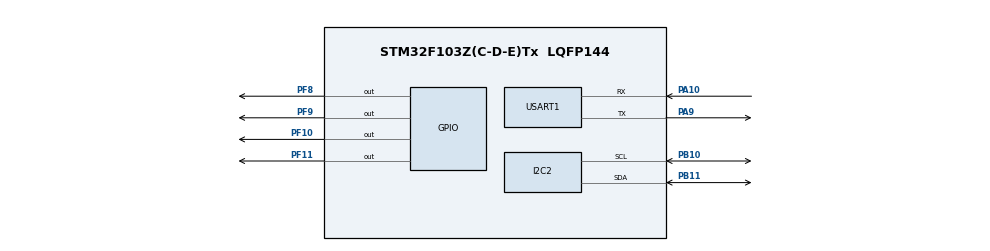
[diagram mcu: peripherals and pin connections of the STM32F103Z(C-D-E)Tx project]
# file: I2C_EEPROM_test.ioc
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I2C2.I2C_Mode=I2C_Fast
Mcu.Family=STM32F1
Mcu.Name=STM32F103Z(C-D-E)Tx
Mcu.Package=LQFP144
NVIC.PriorityGroup=NVIC_PRIORITYGROUP_4
OSC_IN.Mode=HSE-External-Oscillator
OSC_IN.Signal=RCC_OSC_IN
OSC_OUT.Mode=HSE-External-Oscillator
OSC_OUT.Signal=RCC_OSC_OUT
PA10.Mode=Asynchronous
PA10.Signal=USART1_RX
PA13.Mode=Serial_Wire
PA13.Signal=SYS_JTMS-SWDIO
PA14.Mode=Serial_Wire
PA14.Signal=SYS_JTCK-SWCLK
PA9.Mode=Asynchronous
PA9.Signal=USART1_TX
PB10.Mode=I2C
PB10.Signal=I2C2_SCL
PB11.Mode=I2C
PB11.Signal=I2C2_SDA
PF10.GPIO_ModeDefaultOutputPP=GPIO_MODE_OUTPUT_OD
PF10.GPIO_PuPd=GPIO_NOPULL
PF10.PinState=GPIO_PIN_SET
PF10.Signal=GPIO_Output
PF11.GPIO_ModeDefaultOutputPP=GPIO_MODE_OUTPUT_OD
PF11.GPIO_PuPd=GPIO_NOPULL
PF11.PinState=GPIO_PIN_SET
PF11.Signal=GPIO_Output
PF8.GPIO_ModeDefaultOutputPP=GPIO_MODE_OUTPUT_OD
PF8.GPIO_PuPd=GPIO_NOPULL
PF8.PinState=GPIO_PIN_SET
PF8.Signal=GPIO_Output
PF9.GPIO_ModeDefaultOutputPP=GPIO_MODE_OUTPUT_OD
PF9.GPIO_PuPd=GPIO_NOPULL
PF9.PinState=GPIO_PIN_SET
PF9.Signal=GPIO_Output
ProjectManager.HeapSize=0x200
ProjectManager.StackSize=0x400
ProjectManager.TargetToolchain=MDK-ARM V5.32
RCC.AHBFreq_Value=72000000
RCC.APB1CLKDivider=RCC_HCLK_DIV2
RCC.APB1Freq_Value=36000000
RCC.APB1TimFreq_Value=72000000
RCC.APB2Freq_Value=72000000
RCC.APB2TimFreq_Value=72000000
RCC.HCLKFreq_Value=72000000
RCC.PLLMUL=RCC_PLL_MUL9
RCC.PLLSourceVirtual=RCC_PLLSOURCE_HSE
RCC.SYSCLKFreq_VALUE=72000000
RCC.SYSCLKSource=RCC_SYSCLKSOURCE_PLLCLK
RCC.USBFreq_Value=72000000
USART1.Parity=PARITY_ODD
USART1.VirtualMode=VM_ASYNC
USART1.WordLength=WORDLENGTH_9B
board=custom

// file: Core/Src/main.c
/* USER CODE BEGIN Header */
/**
  ******************************************************************************
  * @file           : main.c
  * @brief          : Main program body
  ******************************************************************************
  * @attention
  *
  * Copyright (c) 2026 STMicroelectronics.
  * All rights reserved.
  *
  * This software is licensed under terms that can be found in the LICENSE file
  * in the root directory of this software component.
  * If no LICENSE file comes with this software, it is provided AS-IS.
  *
  ******************************************************************************
  */
/* USER CODE END Header */
#include "main.h"

/* USER CODE BEGIN Includes */
#include "APP.h"
/* USER CODE END Includes */

I2C_HandleTypeDef hi2c2;

UART_HandleTypeDef huart1;

void SystemClock_Config(void);
static void MX_GPIO_Init(void);
static void MX_I2C2_Init(void);
static void MX_USART1_UART_Init(void);

int main(void)
{

  /* MCU Configuration--------------------------------------------------------*/

  /* Reset of all peripherals, Initializes the Flash interface and the Systick. */
  HAL_Init();

  /* Configure the system clock */
  SystemClock_Config();

  /* Initialize all configured peripherals */
  MX_GPIO_Init();
  MX_I2C2_Init();
  MX_USART1_UART_Init();
  /* USER CODE BEGIN 2 */
  BSP_Usart_Init(&huart1);
  App_Init();
  /* USER CODE END 2 */

  /* Infinite loop */
  while (1)
  {

  }
}

void SystemClock_Config(void)
{
  RCC_OscInitTypeDef RCC_OscInitStruct = {0};
  RCC_ClkInitTypeDef RCC_ClkInitStruct = {0};

  /** Initializes the RCC Oscillators according to the specified parameters
  * in the RCC_OscInitTypeDef structure.
  */
  RCC_OscInitStruct.OscillatorType = RCC_OSCILLATORTYPE_HSI;
  RCC_OscInitStruct.HSIState = RCC_HSI_ON;
  RCC_OscInitStruct.HSEState = RCC_HSE_OFF;
  RCC_OscInitStruct.PLL.PLLState = RCC_PLL_ON;
  RCC_OscInitStruct.PLL.PLLSource = RCC_PLLSOURCE_HSI_DIV2;
  RCC_OscInitStruct.PLL.PLLMUL = RCC_PLL_MUL16;
  if (HAL_RCC_OscConfig(&RCC_OscInitStruct) != HAL_OK)
  {
    Error_Handler();
  }

  /** Initializes the CPU, AHB and APB buses clocks
  */
  RCC_ClkInitStruct.ClockType = RCC_CLOCKTYPE_HCLK|RCC_CLOCKTYPE_SYSCLK
                              |RCC_CLOCKTYPE_PCLK1|RCC_CLOCKTYPE_PCLK2;
  RCC_ClkInitStruct.SYSCLKSource = RCC_SYSCLKSOURCE_PLLCLK;
  RCC_ClkInitStruct.AHBCLKDivider = RCC_SYSCLK_DIV1;
  RCC_ClkInitStruct.APB1CLKDivider = RCC_HCLK_DIV2;
  RCC_ClkInitStruct.APB2CLKDivider = RCC_HCLK_DIV1;

  if (HAL_RCC_ClockConfig(&RCC_ClkInitStruct, FLASH_LATENCY_2) != HAL_OK)
  {
    Error_Handler();
  }
}

static void MX_I2C2_Init(void)
{

  hi2c2.Instance = I2C2;
  hi2c2.Init.ClockSpeed = 400000;
  hi2c2.Init.DutyCycle = I2C_DUTYCYCLE_2;
  hi2c2.Init.OwnAddress1 = 0;
  hi2c2.Init.AddressingMode = I2C_ADDRESSINGMODE_7BIT;
  hi2c2.Init.DualAddressMode = I2C_DUALADDRESS_DISABLE;
  hi2c2.Init.OwnAddress2 = 0;
  hi2c2.Init.GeneralCallMode = I2C_GENERALCALL_DISABLE;
  hi2c2.Init.NoStretchMode = I2C_NOSTRETCH_DISABLE;
  if (HAL_I2C_Init(&hi2c2) != HAL_OK)
  {
    Error_Handler();
  }

}

static void MX_USART1_UART_Init(void)
{

  huart1.Instance = USART1;
  huart1.Init.BaudRate = 115200;
  huart1.Init.WordLength = UART_WORDLENGTH_9B;
  huart1.Init.StopBits = UART_STOPBITS_1;
  huart1.Init.Parity = UART_PARITY_NONE;
  huart1.Init.Mode = UART_MODE_TX_RX;
  huart1.Init.HwFlowCtl = UART_HWCONTROL_NONE;
  huart1.Init.OverSampling = UART_OVERSAMPLING_16;
  if (HAL_UART_Init(&huart1) != HAL_OK)
  {
    Error_Handler();
  }

}

static void MX_GPIO_Init(void)
{
  GPIO_InitTypeDef GPIO_InitStruct = {0};

  /* GPIO Ports Clock Enable */
  __HAL_RCC_GPIOF_CLK_ENABLE();
  __HAL_RCC_GPIOB_CLK_ENABLE();
  __HAL_RCC_GPIOA_CLK_ENABLE();

  /*Configure GPIO pin Output Level */
  HAL_GPIO_WritePin(GPIOF, GPIO_PIN_8|GPIO_PIN_9|GPIO_PIN_10|GPIO_PIN_11, GPIO_PIN_SET);

  /*Configure GPIO pins : PF8 PF9 PF10 PF11 */
  GPIO_InitStruct.Pin = GPIO_PIN_8|GPIO_PIN_9|GPIO_PIN_10|GPIO_PIN_11;
  GPIO_InitStruct.Mode = GPIO_MODE_OUTPUT_OD;
  GPIO_InitStruct.Pull = GPIO_NOPULL;
  GPIO_InitStruct.Speed = GPIO_SPEED_FREQ_LOW;
  HAL_GPIO_Init(GPIOF, &GPIO_InitStruct);

}

void Error_Handler(void)
{
  __disable_irq();
  while (1)
  {
  }
}
